VERSION 5.7 ;
NOWIREEXTENSIONATPIN ON ;
DIVIDERCHAR "/" ;
BUSBITCHARS "[]" ;
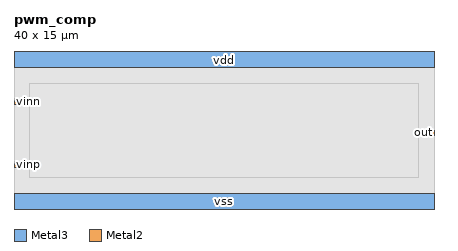
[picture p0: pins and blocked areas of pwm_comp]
MACRO pwm_comp
  CLASS BLOCK ;
  FOREIGN pwm_comp ;
  ORIGIN 0.000 0.000 ;
  SIZE 40.000 BY 15.000 ;
  OBS
    LAYER Metal1 ; RECT 0.000 0.000 40.000 15.000 ;
    LAYER Metal2 ; RECT 1.500 3.000 38.500 12.000 ;
    LAYER Metal3 ; RECT 1.500 3.000 38.500 12.000 ;
  END
  PIN vdd
    DIRECTION INOUT ; USE POWER ; PORT LAYER Metal3 ; RECT 0.000 13.500 40.000 15.000 ; END
  END vdd
  PIN vss
    DIRECTION INOUT ; USE GROUND ; PORT LAYER Metal3 ; RECT 0.000 0.000 40.000 1.500 ; END
  END vss
  PIN vinp
    DIRECTION INPUT ; USE SIGNAL ; PORT LAYER Metal2 ; RECT 0.000 4.000 0.500 4.500 ; END
  END vinp
  PIN vinn
    DIRECTION INPUT ; USE SIGNAL ; PORT LAYER Metal2 ; RECT 0.000 10.000 0.500 10.500 ; END
  END vinn
  PIN out
    DIRECTION OUTPUT ; USE SIGNAL ; PORT LAYER Metal2 ; RECT 39.500 7.000 40.000 7.500 ; END
  END out
END pwm_comp
END LIBRARY
EOF
